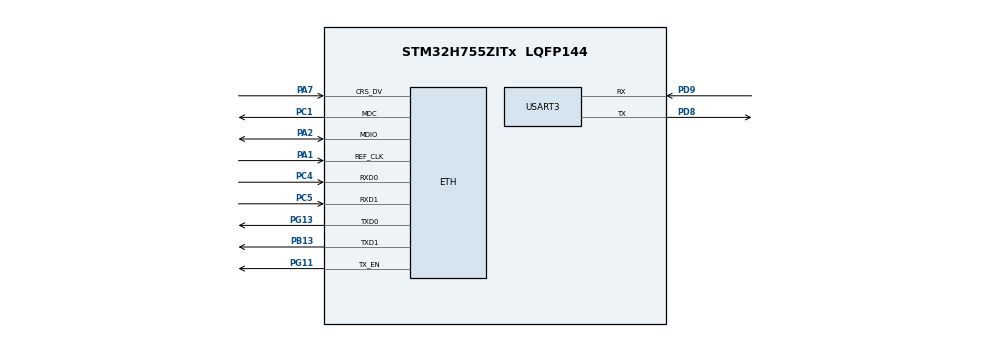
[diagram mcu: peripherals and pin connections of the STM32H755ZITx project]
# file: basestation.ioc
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CortexM4.IPs=CORTEX_M4\:I,FATFS_M4\:I,FREERTOS_M4\:I,IWDG2\:I,OPENAMP_M4\:I,PDM2PCM_M4\:I,PWR,RCC,RESMGR_UTILITY,SYS_M4\:I,USB_DEVICE_M4\:I,USB_HOST_M4\:I,VREFBUF,WWDG2\:I,GPIO,DMA,BDMA,MDMA,NVIC2\:I,ETH
CortexM7.IPs=CORTEX_M7\:I,FATFS_M7\:I,FREERTOS_M7\:I,IWDG1\:I,OPENAMP_M7\:I,PDM2PCM_M7\:I,PWR\:I,RCC\:I,RESMGR_UTILITY\:I,SYS\:I,USB_DEVICE_M7\:I,USB_HOST_M7\:I,VREFBUF\:I,WWDG1\:I,GPIO\:I,DMA\:I,BDMA\:I,MDMA\:I,NVIC1\:I,ETH\:I,USART3\:I,LWIP\:I
ETH.MediaInterface=HAL_ETH_RMII_MODE
ETH.TxDescAddress=0x30000200
LWIP.BSP.number=1
LWIP.Version=v2.1.2_Cube
LWIP0.BSP.STBoard=false
LWIP0.BSP.api=BSP_COMPONENT_DRIVER
LWIP0.BSP.component=LAN8742
LWIP0.BSP.instance=LAN8742
LWIP0.BSP.name=Driver_PHY
LWIP0.BSP.semaphore=S_LAN8742
LWIP0.BSP.solution=LAN8742
Mcu.Family=STM32H7
Mcu.Name=STM32H755ZITx
Mcu.Package=LQFP144
NVIC1.ETH_IRQn=true\:0\:0\:false\:false\:true\:true\:true\:true
NVIC1.PriorityGroup=NVIC_PRIORITYGROUP_4
NVIC2.PriorityGroup=NVIC_PRIORITYGROUP_4
PA1.Mode=RMII
PA1.PinAttribute=CortexM7
PA1.Signal=ETH_REF_CLK
PA2.Mode=RMII
PA2.PinAttribute=CortexM7
PA2.Signal=ETH_MDIO
PA7.Mode=RMII
PA7.PinAttribute=CortexM7
PA7.Signal=ETH_CRS_DV
PB13.Mode=RMII
PB13.PinAttribute=CortexM7
PB13.Signal=ETH_TXD1
PC1.Mode=RMII
PC1.PinAttribute=CortexM7
PC1.Signal=ETH_MDC
PC4.Mode=RMII
PC4.PinAttribute=CortexM7
PC4.Signal=ETH_RXD0
PC5.Mode=RMII
PC5.PinAttribute=CortexM7
PC5.Signal=ETH_RXD1
PD8.Mode=Asynchronous
PD8.PinAttribute=CortexM7
PD8.Signal=USART3_TX
PD9.Mode=Asynchronous
PD9.PinAttribute=CortexM7
PD9.Signal=USART3_RX
PG11.Mode=RMII
PG11.PinAttribute=CortexM7
PG11.Signal=ETH_TX_EN
PG13.Mode=RMII
PG13.PinAttribute=CortexM7
PG13.Signal=ETH_TXD0
ProjectManager.HeapSize=M4-0x200,M7-0x200
ProjectManager.StackSize=M4-0x400,M7-0x400
ProjectManager.TargetToolchain=Makefile
RCC.ADCFreq_Value=129000000
RCC.APB1Freq_Value=120000000
RCC.APB2Freq_Value=120000000
RCC.APB3Freq_Value=120000000
RCC.APB4Freq_Value=120000000
RCC.CortexFreq_Value=480000000
RCC.D1PPRE=RCC_APB3_DIV2
RCC.D2PPRE1=RCC_APB1_DIV2
RCC.D2PPRE2=RCC_APB2_DIV2
RCC.D3PPRE=RCC_APB4_DIV2
RCC.DIVM1=4
RCC.DIVN1=60
RCC.HCLKFreq_Value=240000000
RCC.HPRE=RCC_HCLK_DIV2
RCC.PLL2FRACN=0
RCC.PLL3FRACN=0
RCC.PLLFRACN=0
RCC.SYSCLKFreq_VALUE=480000000
RCC.SYSCLKSource=RCC_SYSCLKSOURCE_PLLCLK
RCC.USBFreq_Value=480000000
SYS.userName=SYS_M7
USART3.VirtualMode-Asynchronous=VM_ASYNC
VP_LWIP_VS_Enabled.Mode=Enabled
VP_SYS_M4_VS_Systick.Mode=SysTick
board=custom

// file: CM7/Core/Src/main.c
/* USER CODE BEGIN Header */
/**
  ******************************************************************************
  * @file           : main.c
  * @brief          : Main program body
  ******************************************************************************
  * @attention
  *
  * Copyright (c) 2024 STMicroelectronics.
  * All rights reserved.
  *
  * This software is licensed under terms that can be found in the LICENSE file
  * in the root directory of this software component.
  * If no LICENSE file comes with this software, it is provided AS-IS.
  *
  ******************************************************************************
  */
/* USER CODE END Header */
#include "main.h"
#include "lwip.h"

/* USER CODE BEGIN PD */

#ifndef HSEM_ID_0
#define HSEM_ID_0 (0U) /* HW semaphore 0*/
#endif

/* USER CODE END PD */

UART_HandleTypeDef huart3;

void SystemClock_Config(void);
static void MX_GPIO_Init(void);
static void MX_USART3_UART_Init(void);

/* USER CODE BEGIN 0 */
#define PUTCHAR_PROTOTYPE int __io_putchar(int ch)
PUTCHAR_PROTOTYPE
{
  HAL_UART_Transmit(&huart3, (uint8_t *)&ch, 1, HAL_MAX_DELAY);
  return ch;
}

int _write(int fd, char *ch, int len)
{
  HAL_UART_Transmit(&huart3, (uint8_t *)ch, len, HAL_MAX_DELAY);
  return len;
}
/* USER CODE END 0 */

int main(void)
{

/* USER CODE BEGIN Boot_Mode_Sequence_0 */
/* USER CODE END Boot_Mode_Sequence_0 */

/* USER CODE BEGIN Boot_Mode_Sequence_1 */

/* USER CODE END Boot_Mode_Sequence_1 */
  /* MCU Configuration--------------------------------------------------------*/

  /* Reset of all peripherals, Initializes the Flash interface and the Systick. */
  HAL_Init();

  /* Configure the system clock */
  SystemClock_Config();
/* USER CODE BEGIN Boot_Mode_Sequence_2 */
  __HAL_RCC_HSEM_CLK_ENABLE();
  HAL_HSEM_FastTake(HSEM_ID_0);
  HAL_HSEM_Release(HSEM_ID_0,0);

  /* wait until CPU2 wakes up from stop mode */
  int32_t timeout = 0xFFFF;
  while((__HAL_RCC_GET_FLAG(RCC_FLAG_D2CKRDY) == RESET) && (timeout-- > 0));
  if ( timeout < 0 )
  {
    Error_Handler();
  }
/* USER CODE END Boot_Mode_Sequence_2 */

  /* Initialize all configured peripherals */
  MX_GPIO_Init();
  MX_USART3_UART_Init();
  MX_LWIP_Init();
  /* USER CODE BEGIN 2 */
  printf("\r\n\r\nbasestation\r\n");
  HAL_GPIO_TogglePin(LED_YELLOW_GPIO_Port, LED_YELLOW_Pin);
  /* USER CODE END 2 */

  /* Infinite loop */
  /* USER CODE BEGIN WHILE */
  while (1)
  {
    MX_LWIP_Process();
    /* USER CODE END WHILE */

  }
}

void SystemClock_Config(void)
{
  RCC_OscInitTypeDef RCC_OscInitStruct = {0};
  RCC_ClkInitTypeDef RCC_ClkInitStruct = {0};

  /** Supply configuration update enable
  */
  HAL_PWREx_ConfigSupply(PWR_DIRECT_SMPS_SUPPLY);

  /** Configure the main internal regulator output voltage
  */
  __HAL_PWR_VOLTAGESCALING_CONFIG(PWR_REGULATOR_VOLTAGE_SCALE1);

  while(!__HAL_PWR_GET_FLAG(PWR_FLAG_VOSRDY)) {}

  /** Initializes the RCC Oscillators according to the specified parameters
  * in the RCC_OscInitTypeDef structure.
  */
  RCC_OscInitStruct.OscillatorType = RCC_OSCILLATORTYPE_HSI;
  RCC_OscInitStruct.HSIState = RCC_HSI_DIV1;
  RCC_OscInitStruct.HSICalibrationValue = RCC_HSICALIBRATION_DEFAULT;
  RCC_OscInitStruct.PLL.PLLState = RCC_PLL_ON;
  RCC_OscInitStruct.PLL.PLLSource = RCC_PLLSOURCE_HSI;
  RCC_OscInitStruct.PLL.PLLM = 4;
  RCC_OscInitStruct.PLL.PLLN = 50;
  RCC_OscInitStruct.PLL.PLLP = 2;
  RCC_OscInitStruct.PLL.PLLQ = 2;
  RCC_OscInitStruct.PLL.PLLR = 2;
  RCC_OscInitStruct.PLL.PLLRGE = RCC_PLL1VCIRANGE_3;
  RCC_OscInitStruct.PLL.PLLVCOSEL = RCC_PLL1VCOWIDE;
  RCC_OscInitStruct.PLL.PLLFRACN = 0;
  if (HAL_RCC_OscConfig(&RCC_OscInitStruct) != HAL_OK)
  {
    Error_Handler();
  }

  /** Initializes the CPU, AHB and APB buses clocks
  */
  RCC_ClkInitStruct.ClockType = RCC_CLOCKTYPE_HCLK|RCC_CLOCKTYPE_SYSCLK
                              |RCC_CLOCKTYPE_PCLK1|RCC_CLOCKTYPE_PCLK2
                              |RCC_CLOCKTYPE_D3PCLK1|RCC_CLOCKTYPE_D1PCLK1;
  RCC_ClkInitStruct.SYSCLKSource = RCC_SYSCLKSOURCE_PLLCLK;
  RCC_ClkInitStruct.SYSCLKDivider = RCC_SYSCLK_DIV1;
  RCC_ClkInitStruct.AHBCLKDivider = RCC_HCLK_DIV2;
  RCC_ClkInitStruct.APB3CLKDivider = RCC_APB3_DIV2;
  RCC_ClkInitStruct.APB1CLKDivider = RCC_APB1_DIV2;
  RCC_ClkInitStruct.APB2CLKDivider = RCC_APB2_DIV2;
  RCC_ClkInitStruct.APB4CLKDivider = RCC_APB4_DIV2;

  if (HAL_RCC_ClockConfig(&RCC_ClkInitStruct, FLASH_LATENCY_2) != HAL_OK)
  {
    Error_Handler();
  }
}

static void MX_USART3_UART_Init(void)
{

  huart3.Instance = USART3;
  huart3.Init.BaudRate = 115200;
  huart3.Init.WordLength = UART_WORDLENGTH_8B;
  huart3.Init.StopBits = UART_STOPBITS_1;
  huart3.Init.Parity = UART_PARITY_NONE;
  huart3.Init.Mode = UART_MODE_TX_RX;
  huart3.Init.HwFlowCtl = UART_HWCONTROL_NONE;
  huart3.Init.OverSampling = UART_OVERSAMPLING_16;
  huart3.Init.OneBitSampling = UART_ONE_BIT_SAMPLE_DISABLE;
  huart3.Init.ClockPrescaler = UART_PRESCALER_DIV1;
  huart3.AdvancedInit.AdvFeatureInit = UART_ADVFEATURE_NO_INIT;
  if (HAL_UART_Init(&huart3) != HAL_OK)
  {
    Error_Handler();
  }
  if (HAL_UARTEx_SetTxFifoThreshold(&huart3, UART_TXFIFO_THRESHOLD_1_8) != HAL_OK)
  {
    Error_Handler();
  }
  if (HAL_UARTEx_SetRxFifoThreshold(&huart3, UART_RXFIFO_THRESHOLD_1_8) != HAL_OK)
  {
    Error_Handler();
  }
  if (HAL_UARTEx_DisableFifoMode(&huart3) != HAL_OK)
  {
    Error_Handler();
  }

}

static void MX_GPIO_Init(void)
{
  GPIO_InitTypeDef GPIO_InitStruct = {0};

  /* GPIO Ports Clock Enable */
  __HAL_RCC_GPIOC_CLK_ENABLE();
  __HAL_RCC_GPIOA_CLK_ENABLE();
  __HAL_RCC_GPIOB_CLK_ENABLE();
  __HAL_RCC_GPIOD_CLK_ENABLE();
  __HAL_RCC_GPIOG_CLK_ENABLE();
  __HAL_RCC_GPIOE_CLK_ENABLE();

  /*Configure GPIO pin Output Level */
  HAL_GPIO_WritePin(LED_RED_GPIO_Port, LED_RED_Pin, GPIO_PIN_RESET);

  /*Configure GPIO pin Output Level */
  HAL_GPIO_WritePin(LED_YELLOW_GPIO_Port, LED_YELLOW_Pin, GPIO_PIN_RESET);

  /*Configure GPIO pin : LED_RED_Pin */
  GPIO_InitStruct.Pin = LED_RED_Pin;
  GPIO_InitStruct.Mode = GPIO_MODE_OUTPUT_PP;
  GPIO_InitStruct.Pull = GPIO_NOPULL;
  GPIO_InitStruct.Speed = GPIO_SPEED_FREQ_LOW;
  HAL_GPIO_Init(LED_RED_GPIO_Port, &GPIO_InitStruct);

  /*Configure GPIO pin : LED_YELLOW_Pin */
  GPIO_InitStruct.Pin = LED_YELLOW_Pin;
  GPIO_InitStruct.Mode = GPIO_MODE_OUTPUT_PP;
  GPIO_InitStruct.Pull = GPIO_NOPULL;
  GPIO_InitStruct.Speed = GPIO_SPEED_FREQ_LOW;
  HAL_GPIO_Init(LED_YELLOW_GPIO_Port, &GPIO_InitStruct);

}

void Error_Handler(void)
{
  /* USER CODE BEGIN Error_Handler_Debug */
  /* User can add his own implementation to report the HAL error return state */
  __disable_irq();
  HAL_GPIO_TogglePin(LED_RED_GPIO_Port, LED_RED_Pin);
  while (1)
  {
  }
  /* USER CODE END Error_Handler_Debug */
}
